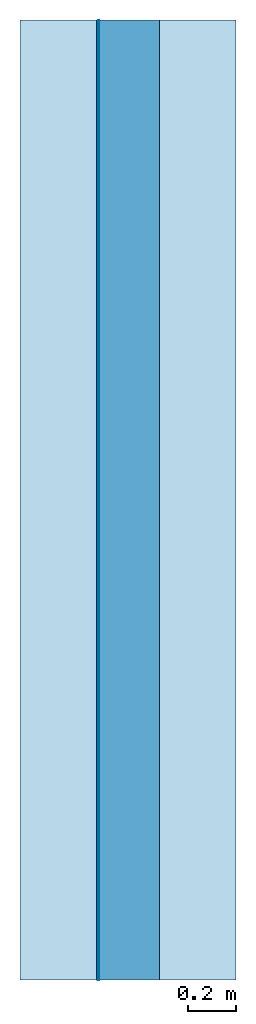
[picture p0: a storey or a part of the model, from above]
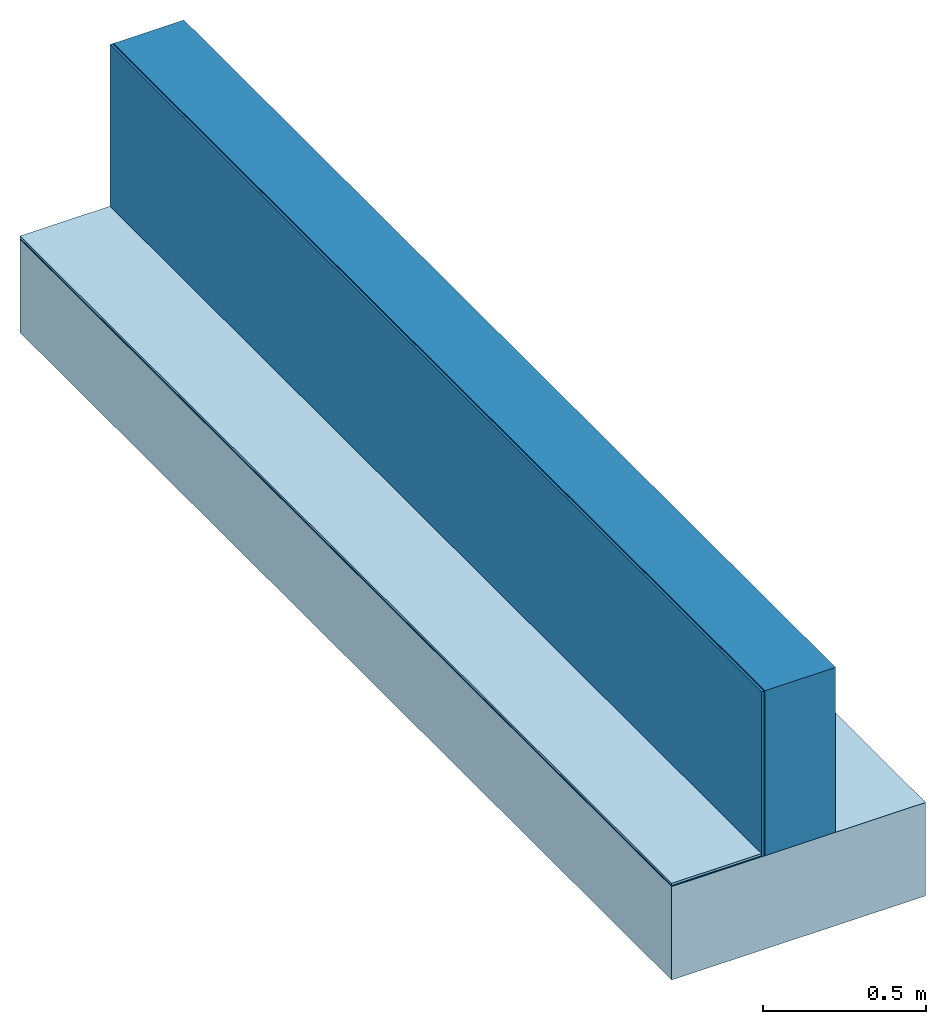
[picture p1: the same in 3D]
Properties of the parts of a building model (IFC2X3)

# File
Description: ViewDefinition [CoordinationView_V2.0]
File name: 0001
Time: 2021-03-09T12:09:19
Written by: The EXPRESS Data Manager Version 5.02.0100.07 : 28 Aug 2013
Made in: 20190108_1515(x64) - Exporter 19.2.1.1 - IU alternativa 19.2.1.1
Comment: STEP Physical File produced by: The EXPRESS Data Manager Version 5.02.0100.07 : 28 Aug 2013 * Module: EDMstepFileFactory/EDMstandAlone * Creation date: Tue Mar 09 12:09:19 2021 * Host: DESKTOP-9PSOHM7 * Database: C:\Users\MODELA~1\AppData\Local\Temp\{B3189705-2D28-454E-AB2C-BD6AF67F8820}\ifc * Database version: 5507 * Database creation date: Tue Mar 09 12:09:18 2021 * Schema: IFC2X3 * Model: DataRepository.ifc * Model creation date: Tue Mar 09 12:09:19 2021 * Header model: DataRepository.ifc_HeaderModel * Header model creation date: Tue Mar 09 12:09:19 2021 * EDMuser: sdai-user * EDMgroup: sdai-group * License ID and type: 5605 : Permanent license. Expiry date: * EDMstepFileFactory options: 020000

# IfcProject, 0001
LongName: Nombre de proyecto; Phase: Estado de proyecto

# IfcSite, Default
RefLatitude: 40, 24, 0, 5493; RefLongitude: -3, -40, -59, -880065; RefElevation: 0 mm

# IfcBuilding
Pset_BuildingCommon - NumberOfStoreys: 1

# IfcBuildingStorey, Nivel 1
LongName: Nivel 1; Elevation: 0 mm

# IfcFooting: Cimentación de muro:ZapataCorrida, Cimentación de muro:ZapataCorrida:140860
In: Nivel 1
PredefinedType: STRIP_FOOTING; Classification: A1010110 Strip Footings (Uniformat); Material: Hormigón, moldeado in situ

# IfcSlab (3)
In: Nivel 1
Pset_SlabCommon - Reference: Pieza; IsExternal: no; PitchAngle: 0 deg
Name (Pieza:...) | Material
144497 | IM_PolietilenoAltaDensidadyGeotextil_Lamina_ChovaDrenDD
144498 | IM_LaminaAsfaltica_Lamina_PolitaberPolPy30 (LBM 30-FP)
144499 | IM_EmulsionBituminosa_Bote_Supermul

# IfcWall (4)
In: Nivel 1
Pset_WallCommon - Reference: Pieza; IsExternal: no; LoadBearing: no; ExtendToStructure: no
Name (Pieza:...) | Material
144507 | IM_PolietilenoAltaDensidadyGeotextil_Lamina_ChovaDrenDD
144508 | IM_LaminaAsfaltica_Lamina_PolitaberPolPy30 (LBM 30-FP)
144509 | IM_EmulsionBituminosa_Bote_Supermul
144510 | Soporte resistente
